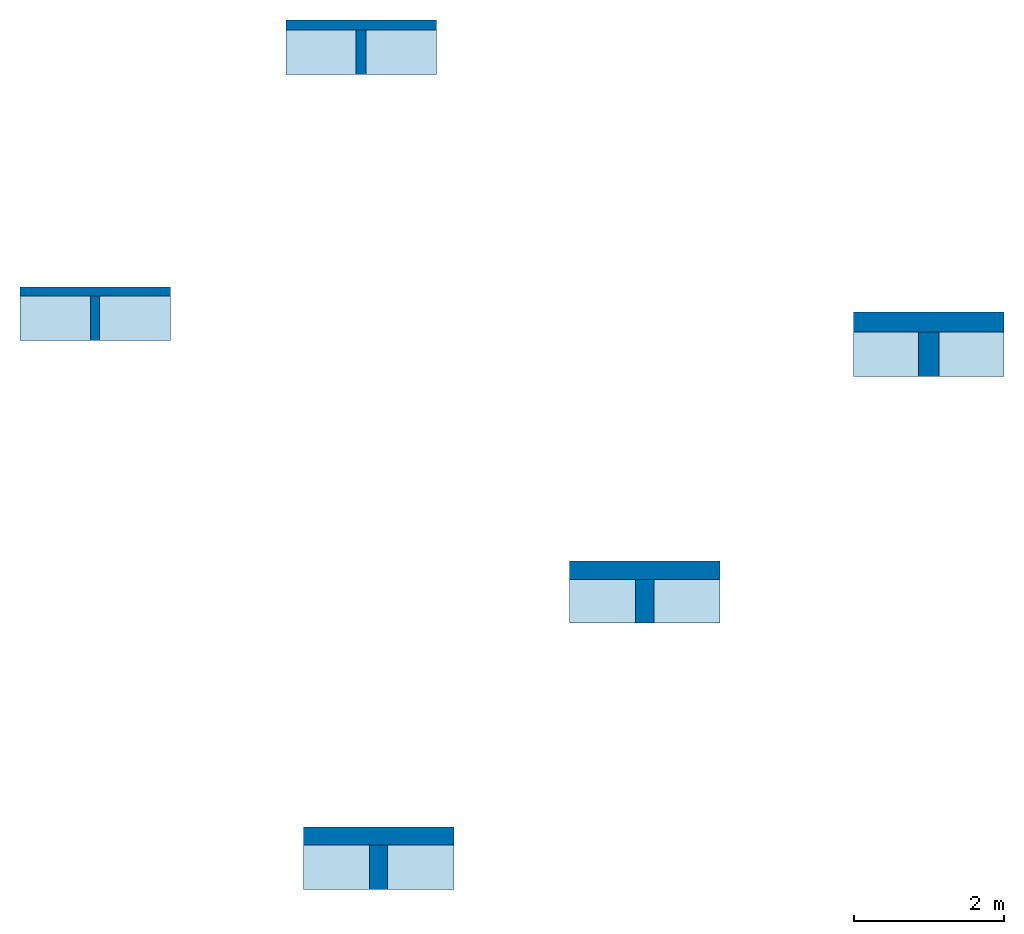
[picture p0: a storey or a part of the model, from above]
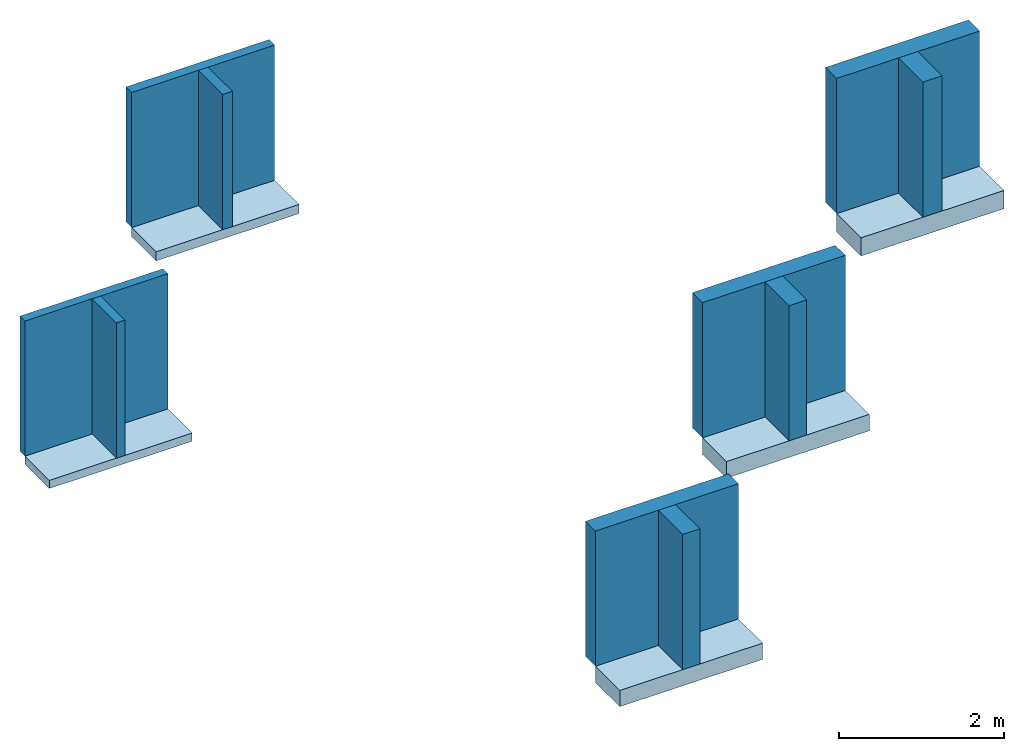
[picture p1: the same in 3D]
Properties of the parts of a building model (IFC2X3)

# File
Description: ViewDefinition [CoordinationView]
Time: 2023-01-18T10:33:11
Written by: The EXPRESS Data Manager Version 5.02.0100.07 : 28 Aug 2013
Made in: 21.1.70.21 - Exporter 21.1.70.21 - Alternate UI 21.1.70.21
Comment: STEP Physical File produced by: The EXPRESS Data Manager Version 5.02.0100.07 : 28 Aug 2013 * Module: EDMstepFileFactory/EDMstandAlone * Creation date: Wed Jan 18 10:33:11 2023 * Host: BIM-LT03 * Database: C:\Users\DONNEE~1\AppData\Local\Temp\6dfd9f73-01cb-4fe2-bb7c-203e315a706e\736068cb-28a9-4118-ab43-d0cfa3a6a8f2\ifc * Database version: 5507 * Database creation date: Wed Jan 18 10:33:10 2023 * Schema: IFC2X3 * Model: DataRepository.ifc * Model creation date: Wed Jan 18 10:33:11 2023 * Header model: DataRepository.ifc_HeaderModel * Header model creation date: Wed Jan 18 10:33:11 2023 * EDMuser: sdai-user * EDMgroup: sdai-group * License ID and type: 5605 : Permanent license. Expiry date: * EDMstepFileFactory options: 020000

# IfcSite, Default
RefLatitude: 42, 24, 53, 508911; RefLongitude: -71, -15, -29, -58837; RefElevation: 0 mm
Pset_ProductRequirements - Category: Project Information

# IfcBuilding
Pset_BuildingCommon - NumberOfStoreys: 2
Pset_ProductRequirements - Category: Project Information

# IfcBuildingStorey: Level:NL_00_niveau (2)
Pset_ProductRequirements - Category: Levels
Name | LongName = Pset_AirSideSystemInformation, Name = Pset_ProductRequirements, Name | Elevation (mm)
Begane grond | Begane grond | 0
Lengte | Lengte | 2000

# IfcRoof: Basic Roof:NLRS_27_RO_Naturoll 033_120x590x3300mm, Basic Roof:NLRS_27_RO_Naturoll 033_120x590x3300mm:5172
In: Lengte
Classification: 27 Daken (Uniformat)
Pset_ElementShading - Roughness: 304.8 mm
Pset_ManufacturerTypeInformation - Manufacturer: Knauf Insulation B.V.
Pset_ProductRequirements - Category: Roofs
Pset_QuantityTakeOff - Reference: Basic Roof:NLRS_27_RO_Naturoll 033_120x590x3300mm
Pset_RoofCommon - IsExternal: yes; Reference: Basic Roof:NLRS_27_RO_Naturoll 033_120x590x3300mm; ProjectedArea: 1.18 m2; TotalArea: 1.18 m2
Pset_Roof Schedule Naturoll 033 LOD400 - rollen / pak: 2; Type: Basic Roof: NLRS_27_RO_Naturoll 033_120x590x3300mm; Assembly Code: 27; Type Image: Raster image: Naturoll 033 .jpg (3); Model: Naturoll 033 is een onbeklede glaswoldeken met ECOSE® Technology; Manufacturer: Knauf Insulation B.V.; URL: www.knaufinsulation.nl; Description: Naturoll 033 - 120mm; phone: +31(0)162-421245; email: customerservice.nl@knaufinsulation.com; product URL: https://www.knaufinsulation.nl/producten-van-knauf-insulation/naturoll-033; warmteweerstand: 3.6; NLRS_C_Code_Brandklasse: A1; warmtegeleidingscoëfficiënt: 0.033; kortstondige waterabsorptie: WS; langdurige waterabsorptie: WL(P); luchtstroomweerstand: Afr10; DoP nummer (Declaration of performance): G4220NPCPR; NLRS_C_content_creator: Knauf Insulation; NLRS_C_content_versie: V1.0; diktebereik: 20 - 370; diktetolerantie: T4; pak (m2): 3.89; pakken / pallet: 24; pallet (m2): 93.36

# IfcRoof: Basic Roof:NLRS_27_RO_Naturoll 033_135x590x3900mm, Basic Roof:NLRS_27_RO_Naturoll 033_135x590x3900mm:5274
In: Lengte
Classification: 27 Daken (Uniformat)
Pset_ElementShading - Roughness: 304.8 mm
Pset_ManufacturerTypeInformation - Manufacturer: Knauf Insulation B.V.
Pset_ProductRequirements - Category: Roofs
Pset_QuantityTakeOff - Reference: Basic Roof:NLRS_27_RO_Naturoll 033_135x590x3900mm
Pset_RoofCommon - IsExternal: yes; Reference: Basic Roof:NLRS_27_RO_Naturoll 033_135x590x3900mm; ProjectedArea: 1.18 m2; TotalArea: 1.18 m2
Pset_Roof Schedule Naturoll 033 LOD400 - rollen / pak: 2; Type: Basic Roof: NLRS_27_RO_Naturoll 033_135x590x3900mm; Assembly Code: 27; Type Image: Raster image: Naturoll 033 .jpg (3); Model: Naturoll 033 is een onbeklede glaswoldeken met ECOSE® Technology; Manufacturer: Knauf Insulation B.V.; URL: www.knaufinsulation.nl; Description: Naturoll 033 - 135mm; phone: +31(0)162-421245; email: customerservice.nl@knaufinsulation.com; product URL: https://www.knaufinsulation.nl/producten-van-knauf-insulation/naturoll-033; warmteweerstand: 4.05; NLRS_C_Code_Brandklasse: A1; warmtegeleidingscoëfficiënt: 0.033; kortstondige waterabsorptie: WS; langdurige waterabsorptie: WL(P); luchtstroomweerstand: Afr10; DoP nummer (Declaration of performance): G4220NPCPR; NLRS_C_content_creator: Knauf Insulation; NLRS_C_content_versie: V1.0; diktebereik: 20 - 370; diktetolerantie: T4; pak (m2): 4.6; pakken / pallet: 24; pallet (m2): 110.45

# IfcRoof: Basic Roof:NLRS_27_RO_Naturoll 033_240x590x2000mm, Basic Roof:NLRS_27_RO_Naturoll 033_240x590x2000mm:11013
In: Lengte
Classification: 27 Daken (Uniformat)
Pset_ElementShading - Roughness: 304.8 mm
Pset_ManufacturerTypeInformation - Manufacturer: Knauf Insulation B.V.
Pset_ProductRequirements - Category: Roofs
Pset_QuantityTakeOff - Reference: Basic Roof:NLRS_27_RO_Naturoll 033_240x590x2000mm
Pset_RoofCommon - IsExternal: yes; Reference: Basic Roof:NLRS_27_RO_Naturoll 033_240x590x2000mm; ProjectedArea: 1.18 m2; TotalArea: 1.18 m2
Pset_Roof Schedule Naturoll 033 LOD400 - rollen / pak: 2; Type: Basic Roof: NLRS_27_RO_Naturoll 033_240x590x2000mm; Assembly Code: 27; Type Image: Raster image: Naturoll 033 .jpg (3); Model: Naturoll 033 is een onbeklede glaswoldeken met ECOSE® Technology; Manufacturer: Knauf Insulation B.V.; URL: www.knaufinsulation.nl; Description: Naturoll 033 - 240mm; phone: +31(0)162-421245; email: customerservice.nl@knaufinsulation.com; product URL: https://www.knaufinsulation.nl/producten-van-knauf-insulation/naturoll-033; warmteweerstand: 7.25; NLRS_C_Code_Brandklasse: A1; warmtegeleidingscoëfficiënt: 0.033; kortstondige waterabsorptie: WS; langdurige waterabsorptie: WL(P); luchtstroomweerstand: Afr10; DoP nummer (Declaration of performance): G4220NPCPR; NLRS_C_content_creator: Knauf Insulation; NLRS_C_content_versie: V1.0; diktebereik: 20 - 370; diktetolerantie: T4; pak (m2): 2.36; pakken / pallet: 24; pallet (m2): 56.64

# IfcRoof: Basic Roof:NLRS_27_RO_Naturoll 033_245x580x2000mm, Basic Roof:NLRS_27_RO_Naturoll 033_245x580x2000mm:11035
In: Lengte
Classification: 27 Daken (Uniformat)
Pset_ElementShading - Roughness: 304.8 mm
Pset_ManufacturerTypeInformation - Manufacturer: Knauf Insulation B.V.
Pset_ProductRequirements - Category: Roofs
Pset_QuantityTakeOff - Reference: Basic Roof:NLRS_27_RO_Naturoll 033_245x580x2000mm
Pset_RoofCommon - IsExternal: yes; Reference: Basic Roof:NLRS_27_RO_Naturoll 033_245x580x2000mm; ProjectedArea: 1.16 m2; TotalArea: 1.16 m2
Pset_Roof Schedule Naturoll 033 LOD400 - rollen / pak: 2; Type: Basic Roof: NLRS_27_RO_Naturoll 033_245x580x2000mm; Assembly Code: 27; Type Image: Raster image: Naturoll 033 .jpg (3); Model: Naturoll 033 is een onbeklede glaswoldeken met ECOSE® Technology; Manufacturer: Knauf Insulation B.V.; URL: www.knaufinsulation.nl; Description: Naturoll 033 - 245mm; phone: +31(0)162-421245; email: customerservice.nl@knaufinsulation.com; product URL: https://www.knaufinsulation.nl/producten-van-knauf-insulation/naturoll-033; warmteweerstand: 7.4; NLRS_C_Code_Brandklasse: A1; warmtegeleidingscoëfficiënt: 0.033; kortstondige waterabsorptie: WS; langdurige waterabsorptie: WL(P); luchtstroomweerstand: Afr10; DoP nummer (Declaration of performance): G4220NPCPR; NLRS_C_content_creator: Knauf Insulation; NLRS_C_content_versie: V1.0; diktebereik: 20 - 370; diktetolerantie: T4; pak (m2): 2.32; pakken / pallet: 24; pallet (m2): 55.68

# IfcRoof: Basic Roof:NLRS_27_RO_Naturoll 033_270x590x2500mm, Basic Roof:NLRS_27_RO_Naturoll 033_270x590x2500mm:11855
In: Lengte
Classification: 27 Daken (Uniformat)
Pset_ElementShading - Roughness: 304.8 mm
Pset_ManufacturerTypeInformation - Manufacturer: Knauf Insulation B.V.
Pset_ProductRequirements - Category: Roofs
Pset_QuantityTakeOff - Reference: Basic Roof:NLRS_27_RO_Naturoll 033_270x590x2500mm
Pset_RoofCommon - IsExternal: yes; Reference: Basic Roof:NLRS_27_RO_Naturoll 033_270x590x2500mm; ProjectedArea: 1.18 m2; TotalArea: 1.18 m2
Pset_Roof Schedule Naturoll 033 LOD400 - rollen / pak: 2; Type: Basic Roof: NLRS_27_RO_Naturoll 033_270x590x2500mm; Assembly Code: 27; Type Image: Raster image: Naturoll 033 .jpg (3); Model: Naturoll 033 is een onbeklede glaswoldeken met ECOSE® Technology; Manufacturer: Knauf Insulation B.V.; URL: www.knaufinsulation.nl; Description: Naturoll 033 - 270mm; phone: +31(0)162-421245; email: customerservice.nl@knaufinsulation.com; product URL: https://www.knaufinsulation.nl/producten-van-knauf-insulation/naturoll-033; warmteweerstand: 8.15; NLRS_C_Code_Brandklasse: A1; warmtegeleidingscoëfficiënt: 0.033; kortstondige waterabsorptie: WS; langdurige waterabsorptie: WL(P); luchtstroomweerstand: Afr10; DoP nummer (Declaration of performance): G4220NPCPR; NLRS_C_content_creator: Knauf Insulation; NLRS_C_content_versie: V1.0; diktebereik: 20 - 370; diktetolerantie: T4; pak (m2): 2.95; pakken / pallet: 18; pallet (m2): 53.1

# IfcSlab: Basic Roof:NLRS_27_RO_Naturoll 033_120x590x3300mm, Basic Roof:NLRS_27_RO_Naturoll 033_120x590x3300mm:5172
In: Lengte
Type - PredefinedType: ROOF
Type - Pset_ElementShading - Roughness: 304.8 mm
Type - Pset_ManufacturerTypeInformation - Manufacturer: Knauf Insulation B.V.
Type - Pset_ProductRequirements - Category: Roofs
Type - Pset_QuantityTakeOff - Reference: Basic Roof:NLRS_27_RO_Naturoll 033_120x590x3300mm
Type - Pset_ReinforcementBarPitchOfSlab - Description: Naturoll 033 - 120mm; Reference: Basic Roof:NLRS_27_RO_Naturoll 033_120x590x3300mm
Type - Pset_SlabCommon - IsExternal: yes; Reference: Basic Roof:NLRS_27_RO_Naturoll 033_120x590x3300mm; ThermalTransmittance: 0.275 kg/K/s3
Type - Pset_Roof Schedule Naturoll 033 LOD400 - rollen / pak: 2; Assembly Code: 27; Type Image: Raster image: Naturoll 033 .jpg (3); Model: Naturoll 033 is een onbeklede glaswoldeken met ECOSE® Technology; Manufacturer: Knauf Insulation B.V.; URL: www.knaufinsulation.nl; Description: Naturoll 033 - 120mm; phone: +31(0)162-421245; email: customerservice.nl@knaufinsulation.com; product URL: https://www.knaufinsulation.nl/producten-van-knauf-insulation/naturoll-033; warmteweerstand: 3.6; NLRS_C_Code_Brandklasse: A1; warmtegeleidingscoëfficiënt: 0.033; kortstondige waterabsorptie: WS; langdurige waterabsorptie: WL(P); luchtstroomweerstand: Afr10; DoP nummer (Declaration of performance): G4220NPCPR; NLRS_C_content_creator: Knauf Insulation; NLRS_C_content_versie: V1.0; diktebereik: 20 - 370; diktetolerantie: T4; pak (m2): 3.89; pakken / pallet: 24; pallet (m2): 93.36
Classification: 27 Daken (Uniformat); Material: Knauf Insulation_Ecose® glaswol Naturoll 033; Knauf Insulation_Ecose® glaswol Naturoll 033 120 mm
Pset_SlabCommon - PitchAngle: 0 deg
Pset_Roof Schedule Naturoll 033 LOD400 - Type: Basic Roof: NLRS_27_RO_Naturoll 033_120x590x3300mm

# IfcSlab: Basic Roof:NLRS_27_RO_Naturoll 033_135x590x3900mm, Basic Roof:NLRS_27_RO_Naturoll 033_135x590x3900mm:5274
In: Lengte
Type - PredefinedType: ROOF
Type - Pset_ElementShading - Roughness: 304.8 mm
Type - Pset_ManufacturerTypeInformation - Manufacturer: Knauf Insulation B.V.
Type - Pset_ProductRequirements - Category: Roofs
Type - Pset_QuantityTakeOff - Reference: Basic Roof:NLRS_27_RO_Naturoll 033_135x590x3900mm
Type - Pset_ReinforcementBarPitchOfSlab - Description: Naturoll 033 - 135mm; Reference: Basic Roof:NLRS_27_RO_Naturoll 033_135x590x3900mm
Type - Pset_SlabCommon - IsExternal: yes; Reference: Basic Roof:NLRS_27_RO_Naturoll 033_135x590x3900mm; ThermalTransmittance: 0.244444 kg/K/s3
Type - Pset_Roof Schedule Naturoll 033 LOD400 - rollen / pak: 2; Assembly Code: 27; Type Image: Raster image: Naturoll 033 .jpg (3); Model: Naturoll 033 is een onbeklede glaswoldeken met ECOSE® Technology; Manufacturer: Knauf Insulation B.V.; URL: www.knaufinsulation.nl; Description: Naturoll 033 - 135mm; phone: +31(0)162-421245; email: customerservice.nl@knaufinsulation.com; product URL: https://www.knaufinsulation.nl/producten-van-knauf-insulation/naturoll-033; warmteweerstand: 4.05; NLRS_C_Code_Brandklasse: A1; warmtegeleidingscoëfficiënt: 0.033; kortstondige waterabsorptie: WS; langdurige waterabsorptie: WL(P); luchtstroomweerstand: Afr10; DoP nummer (Declaration of performance): G4220NPCPR; NLRS_C_content_creator: Knauf Insulation; NLRS_C_content_versie: V1.0; diktebereik: 20 - 370; diktetolerantie: T4; pak (m2): 4.6; pakken / pallet: 24; pallet (m2): 110.45
Classification: 27 Daken (Uniformat); Material: Knauf Insulation_Ecose® glaswol Naturoll 033; Knauf Insulation_Ecose® glaswol Naturoll 033 135 mm
Pset_SlabCommon - PitchAngle: 0 deg
Pset_Roof Schedule Naturoll 033 LOD400 - Type: Basic Roof: NLRS_27_RO_Naturoll 033_135x590x3900mm

# IfcSlab: Basic Roof:NLRS_27_RO_Naturoll 033_240x590x2000mm, Basic Roof:NLRS_27_RO_Naturoll 033_240x590x2000mm:11013
In: Lengte
Type - PredefinedType: ROOF
Type - Pset_ElementShading - Roughness: 304.8 mm
Type - Pset_ManufacturerTypeInformation - Manufacturer: Knauf Insulation B.V.
Type - Pset_ProductRequirements - Category: Roofs
Type - Pset_QuantityTakeOff - Reference: Basic Roof:NLRS_27_RO_Naturoll 033_240x590x2000mm
Type - Pset_ReinforcementBarPitchOfSlab - Description: Naturoll 033 - 240mm; Reference: Basic Roof:NLRS_27_RO_Naturoll 033_240x590x2000mm
Type - Pset_SlabCommon - IsExternal: yes; Reference: Basic Roof:NLRS_27_RO_Naturoll 033_240x590x2000mm; ThermalTransmittance: 0.134694 kg/K/s3
Type - Pset_Roof Schedule Naturoll 033 LOD400 - rollen / pak: 2; Assembly Code: 27; Type Image: Raster image: Naturoll 033 .jpg (3); Model: Naturoll 033 is een onbeklede glaswoldeken met ECOSE® Technology; Manufacturer: Knauf Insulation B.V.; URL: www.knaufinsulation.nl; Description: Naturoll 033 - 240mm; phone: +31(0)162-421245; email: customerservice.nl@knaufinsulation.com; product URL: https://www.knaufinsulation.nl/producten-van-knauf-insulation/naturoll-033; warmteweerstand: 7.25; NLRS_C_Code_Brandklasse: A1; warmtegeleidingscoëfficiënt: 0.033; kortstondige waterabsorptie: WS; langdurige waterabsorptie: WL(P); luchtstroomweerstand: Afr10; DoP nummer (Declaration of performance): G4220NPCPR; NLRS_C_content_creator: Knauf Insulation; NLRS_C_content_versie: V1.0; diktebereik: 20 - 370; diktetolerantie: T4; pak (m2): 2.36; pakken / pallet: 24; pallet (m2): 56.64
Classification: 27 Daken (Uniformat); Material: Knauf Insulation_Ecose® glaswol Naturoll 033; Knauf Insulation_Ecose® glaswol Naturoll 033 245 mm
Pset_SlabCommon - PitchAngle: 0 deg
Pset_Roof Schedule Naturoll 033 LOD400 - Type: Basic Roof: NLRS_27_RO_Naturoll 033_240x590x2000mm

# IfcSlab: Basic Roof:NLRS_27_RO_Naturoll 033_245x580x2000mm, Basic Roof:NLRS_27_RO_Naturoll 033_245x580x2000mm:11035
In: Lengte
Type - PredefinedType: ROOF
Type - Pset_ElementShading - Roughness: 304.8 mm
Type - Pset_ManufacturerTypeInformation - Manufacturer: Knauf Insulation B.V.
Type - Pset_ProductRequirements - Category: Roofs
Type - Pset_QuantityTakeOff - Reference: Basic Roof:NLRS_27_RO_Naturoll 033_245x580x2000mm
Type - Pset_ReinforcementBarPitchOfSlab - Description: Naturoll 033 - 245mm; Reference: Basic Roof:NLRS_27_RO_Naturoll 033_245x580x2000mm
Type - Pset_SlabCommon - IsExternal: yes; Reference: Basic Roof:NLRS_27_RO_Naturoll 033_245x580x2000mm; ThermalTransmittance: 0.134694 kg/K/s3
Type - Pset_Roof Schedule Naturoll 033 LOD400 - rollen / pak: 2; Assembly Code: 27; Type Image: Raster image: Naturoll 033 .jpg (3); Model: Naturoll 033 is een onbeklede glaswoldeken met ECOSE® Technology; Manufacturer: Knauf Insulation B.V.; URL: www.knaufinsulation.nl; Description: Naturoll 033 - 245mm; phone: +31(0)162-421245; email: customerservice.nl@knaufinsulation.com; product URL: https://www.knaufinsulation.nl/producten-van-knauf-insulation/naturoll-033; warmteweerstand: 7.4; NLRS_C_Code_Brandklasse: A1; warmtegeleidingscoëfficiënt: 0.033; kortstondige waterabsorptie: WS; langdurige waterabsorptie: WL(P); luchtstroomweerstand: Afr10; DoP nummer (Declaration of performance): G4220NPCPR; NLRS_C_content_creator: Knauf Insulation; NLRS_C_content_versie: V1.0; diktebereik: 20 - 370; diktetolerantie: T4; pak (m2): 2.32; pakken / pallet: 24; pallet (m2): 55.68
Classification: 27 Daken (Uniformat); Material: Knauf Insulation_Ecose® glaswol Naturoll 033; Knauf Insulation_Ecose® glaswol Naturoll 033 245 mm
Pset_SlabCommon - PitchAngle: 0 deg
Pset_Roof Schedule Naturoll 033 LOD400 - Type: Basic Roof: NLRS_27_RO_Naturoll 033_245x580x2000mm

# IfcSlab: Basic Roof:NLRS_27_RO_Naturoll 033_270x590x2500mm, Basic Roof:NLRS_27_RO_Naturoll 033_270x590x2500mm:11855
In: Lengte
Type - PredefinedType: ROOF
Type - Pset_ElementShading - Roughness: 304.8 mm
Type - Pset_ManufacturerTypeInformation - Manufacturer: Knauf Insulation B.V.
Type - Pset_ProductRequirements - Category: Roofs
Type - Pset_QuantityTakeOff - Reference: Basic Roof:NLRS_27_RO_Naturoll 033_270x590x2500mm
Type - Pset_ReinforcementBarPitchOfSlab - Description: Naturoll 033 - 270mm; Reference: Basic Roof:NLRS_27_RO_Naturoll 033_270x590x2500mm
Type - Pset_SlabCommon - IsExternal: yes; Reference: Basic Roof:NLRS_27_RO_Naturoll 033_270x590x2500mm; ThermalTransmittance: 0.122222 kg/K/s3
Type - Pset_Roof Schedule Naturoll 033 LOD400 - rollen / pak: 2; Assembly Code: 27; Type Image: Raster image: Naturoll 033 .jpg (3); Model: Naturoll 033 is een onbeklede glaswoldeken met ECOSE® Technology; Manufacturer: Knauf Insulation B.V.; URL: www.knaufinsulation.nl; Description: Naturoll 033 - 270mm; phone: +31(0)162-421245; email: customerservice.nl@knaufinsulation.com; product URL: https://www.knaufinsulation.nl/producten-van-knauf-insulation/naturoll-033; warmteweerstand: 8.15; NLRS_C_Code_Brandklasse: A1; warmtegeleidingscoëfficiënt: 0.033; kortstondige waterabsorptie: WS; langdurige waterabsorptie: WL(P); luchtstroomweerstand: Afr10; DoP nummer (Declaration of performance): G4220NPCPR; NLRS_C_content_creator: Knauf Insulation; NLRS_C_content_versie: V1.0; diktebereik: 20 - 370; diktetolerantie: T4; pak (m2): 2.95; pakken / pallet: 18; pallet (m2): 53.1
Classification: 27 Daken (Uniformat); Material: Knauf Insulation_Ecose® glaswol Naturoll 033; Knauf Insulation_Ecose® glaswol Naturoll 033 270 mm
Pset_SlabCommon - PitchAngle: 0 deg
Pset_Roof Schedule Naturoll 033 LOD400 - Type: Basic Roof: NLRS_27_RO_Naturoll 033_270x590x2500mm

# IfcSlab: Floor:NLRS_23_FL_Naturoll 033_120x590x3300mm, Floor:NLRS_23_FL_Naturoll 033_120x590x3300mm:4805
In: Begane grond
Type - PredefinedType: FLOOR; Material: Knauf Insulation_Ecose® glaswol Naturoll 033 120 mm
Type - Pset_ElementShading - Roughness: 304.8 mm
Type - Pset_ManufacturerTypeInformation - Manufacturer: Knauf Insulation B.V.
Type - Pset_ProductRequirements - Category: Floors
Type - Pset_QuantityTakeOff - Reference: Floor:NLRS_23_FL_Naturoll 033_120x590x3300mm
Type - Pset_ReinforcementBarPitchOfSlab - Description: Naturoll 033 - 120mm; Reference: Floor:NLRS_23_FL_Naturoll 033_120x590x3300mm
Type - Pset_SlabCommon - Reference: Floor:NLRS_23_FL_Naturoll 033_120x590x3300mm; IsExternal: no; ThermalTransmittance: 0.275 kg/K/s3
Type - Pset_Floor Schedule Naturoll 033 LOD400 - rollen / pak: 2; Assembly Code: 23; Type Image: Raster image: Naturoll 033 .jpg (3); Model: Naturoll 033 is een onbeklede glaswoldeken met ECOSE® Technology; Manufacturer: Knauf Insulation B.V.; URL: www.knaufinsulation.nl; Description: Naturoll 033 - 120mm; phone: +31(0)162-421245; email: customerservice.nl@knaufinsulation.com; product URL: https://www.knaufinsulation.nl/producten-van-knauf-insulation/naturoll-033; warmteweerstand: 3.6; NLRS_C_Code_Brandklasse: A1; warmtegeleidingscoëfficiënt: 0.033; kortstondige waterabsorptie: WS; langdurige waterabsorptie: WL(P); luchtstroomweerstand: Afr10; DoP nummer (Declaration of performance): G4220NPCPR; NLRS_C_content_creator: Knauf Insulation; NLRS_C_content_versie: V1.0; diktebereik: 20 - 370; diktetolerantie: T4; pak (m2): 3.89; pakken / pallet: 24; pallet (m2): 93.36
Classification: 23 Vloeren (Uniformat)
Pset_SlabCommon - LoadBearing: no; PitchAngle: 0 deg
Pset_Floor Schedule Naturoll 033 LOD400 - Type: Floor: NLRS_23_FL_Naturoll 033_120x590x3300mm

# IfcSlab: Floor:NLRS_23_FL_Naturoll 033_135x590x3900mm, Floor:NLRS_23_FL_Naturoll 033_135x590x3900mm:5263
In: Begane grond
Type - PredefinedType: FLOOR; Material: Knauf Insulation_Ecose® glaswol Naturoll 033 135 mm
Type - Pset_ElementShading - Roughness: 304.8 mm
Type - Pset_ManufacturerTypeInformation - Manufacturer: Knauf Insulation B.V.
Type - Pset_ProductRequirements - Category: Floors
Type - Pset_QuantityTakeOff - Reference: Floor:NLRS_23_FL_Naturoll 033_135x590x3900mm
Type - Pset_ReinforcementBarPitchOfSlab - Description: Naturoll 033 - 135mm; Reference: Floor:NLRS_23_FL_Naturoll 033_135x590x3900mm
Type - Pset_SlabCommon - IsExternal: no; Reference: Floor:NLRS_23_FL_Naturoll 033_135x590x3900mm; ThermalTransmittance: 0.244444 kg/K/s3
Type - Pset_Floor Schedule Naturoll 033 LOD400 - rollen / pak: 2; Assembly Code: 23; Type Image: Raster image: Naturoll 033 .jpg (3); Model: Naturoll 033 is een onbeklede glaswoldeken met ECOSE® Technology; Manufacturer: Knauf Insulation B.V.; URL: www.knaufinsulation.nl; Description: Naturoll 033 - 135mm; phone: +31(0)162-421245; email: customerservice.nl@knaufinsulation.com; product URL: https://www.knaufinsulation.nl/producten-van-knauf-insulation/naturoll-033; warmteweerstand: 4.05; NLRS_C_Code_Brandklasse: A1; warmtegeleidingscoëfficiënt: 0.033; kortstondige waterabsorptie: WS; langdurige waterabsorptie: WL(P); luchtstroomweerstand: Afr10; DoP nummer (Declaration of performance): G4220NPCPR; NLRS_C_content_creator: Knauf Insulation; NLRS_C_content_versie: V1.0; diktebereik: 20 - 370; diktetolerantie: T4; pak (m2): 4.6; pakken / pallet: 24; pallet (m2): 110.45
Classification: 23 Vloeren (Uniformat)
Pset_SlabCommon - LoadBearing: no; PitchAngle: 0 deg
Pset_Floor Schedule Naturoll 033 LOD400 - Type: Floor: NLRS_23_FL_Naturoll 033_135x590x3900mm

# IfcSlab: Floor:NLRS_23_FL_Naturoll 033_240x590x2000mm, Floor:NLRS_23_FL_Naturoll 033_240x590x2000mm:11002
In: Begane grond
Type - PredefinedType: FLOOR; Material: Knauf Insulation_Ecose® glaswol Naturoll 033 240 mm
Type - Pset_ElementShading - Roughness: 304.8 mm
Type - Pset_ManufacturerTypeInformation - Manufacturer: Knauf Insulation B.V.
Type - Pset_ProductRequirements - Category: Floors
Type - Pset_QuantityTakeOff - Reference: Floor:NLRS_23_FL_Naturoll 033_240x590x2000mm
Type - Pset_ReinforcementBarPitchOfSlab - Description: Naturoll 033 - 240mm; Reference: Floor:NLRS_23_FL_Naturoll 033_240x590x2000mm
Type - Pset_SlabCommon - IsExternal: no; Reference: Floor:NLRS_23_FL_Naturoll 033_240x590x2000mm; ThermalTransmittance: 0.1375 kg/K/s3
Type - Pset_Floor Schedule Naturoll 033 LOD400 - rollen / pak: 2; Assembly Code: 23; Type Image: Raster image: Naturoll 033 .jpg (3); Model: Naturoll 033 is een onbeklede glaswoldeken met ECOSE® Technology; Manufacturer: Knauf Insulation B.V.; URL: www.knaufinsulation.nl; Description: Naturoll 033 - 240mm; phone: +31(0)162-421245; email: customerservice.nl@knaufinsulation.com; product URL: https://www.knaufinsulation.nl/producten-van-knauf-insulation/naturoll-033; warmteweerstand: 7.25; NLRS_C_Code_Brandklasse: A1; warmtegeleidingscoëfficiënt: 0.033; kortstondige waterabsorptie: WS; langdurige waterabsorptie: WL(P); luchtstroomweerstand: Afr10; DoP nummer (Declaration of performance): G4220NPCPR; NLRS_C_content_creator: Knauf Insulation; NLRS_C_content_versie: V1.0; diktebereik: 20 - 370; diktetolerantie: T4; pak (m2): 2.36; pakken / pallet: 24; pallet (m2): 56.64
Classification: 23 Vloeren (Uniformat)
Pset_SlabCommon - LoadBearing: no; PitchAngle: 0 deg
Pset_Floor Schedule Naturoll 033 LOD400 - Type: Floor: NLRS_23_FL_Naturoll 033_240x590x2000mm

# IfcSlab: Floor:NLRS_23_FL_Naturoll 033_245x580x2000mm, Floor:NLRS_23_FL_Naturoll 033_245x580x2000mm:11025
In: Begane grond
Type - PredefinedType: FLOOR; Material: Knauf Insulation_Ecose® glaswol Naturoll 033 245 mm
Type - Pset_ElementShading - Roughness: 304.8 mm
Type - Pset_ManufacturerTypeInformation - Manufacturer: Knauf Insulation B.V.
Type - Pset_ProductRequirements - Category: Floors
Type - Pset_QuantityTakeOff - Reference: Floor:NLRS_23_FL_Naturoll 033_245x580x2000mm
Type - Pset_ReinforcementBarPitchOfSlab - Description: Naturoll 033 - 245mm; Reference: Floor:NLRS_23_FL_Naturoll 033_245x580x2000mm
Type - Pset_SlabCommon - IsExternal: no; Reference: Floor:NLRS_23_FL_Naturoll 033_245x580x2000mm; ThermalTransmittance: 0.134694 kg/K/s3
Type - Pset_Floor Schedule Naturoll 033 LOD400 - rollen / pak: 2; Assembly Code: 23; Type Image: Raster image: Naturoll 033 .jpg (3); Model: Naturoll 033 is een onbeklede glaswoldeken met ECOSE® Technology; Manufacturer: Knauf Insulation B.V.; URL: www.knaufinsulation.nl; Description: Naturoll 033 - 245mm; phone: +31(0)162-421245; email: customerservice.nl@knaufinsulation.com; product URL: https://www.knaufinsulation.nl/producten-van-knauf-insulation/naturoll-033; warmteweerstand: 7.4; NLRS_C_Code_Brandklasse: A1; warmtegeleidingscoëfficiënt: 0.033; kortstondige waterabsorptie: WS; langdurige waterabsorptie: WL(P); luchtstroomweerstand: Afr10; DoP nummer (Declaration of performance): G4220NPCPR; NLRS_C_content_creator: Knauf Insulation; NLRS_C_content_versie: V1.0; diktebereik: 20 - 370; diktetolerantie: T4; pak (m2): 2.32; pakken / pallet: 24; pallet (m2): 55.68
Classification: 23 Vloeren (Uniformat)
Pset_SlabCommon - LoadBearing: no; PitchAngle: 0 deg
Pset_Floor Schedule Naturoll 033 LOD400 - Type: Floor: NLRS_23_FL_Naturoll 033_245x580x2000mm

# IfcSlab: Floor:NLRS_23_FL_Naturoll 033_270x590x2500mm, Floor:NLRS_23_FL_Naturoll 033_270x590x2500mm:11844
In: Begane grond
Type - PredefinedType: FLOOR; Material: Knauf Insulation_Ecose® glaswol Naturoll 033 270 mm
Type - Pset_ElementShading - Roughness: 304.8 mm
Type - Pset_ManufacturerTypeInformation - Manufacturer: Knauf Insulation B.V.
Type - Pset_ProductRequirements - Category: Floors
Type - Pset_QuantityTakeOff - Reference: Floor:NLRS_23_FL_Naturoll 033_270x590x2500mm
Type - Pset_ReinforcementBarPitchOfSlab - Description: Naturoll 033 - 270mm; Reference: Floor:NLRS_23_FL_Naturoll 033_270x590x2500mm
Type - Pset_SlabCommon - IsExternal: no; Reference: Floor:NLRS_23_FL_Naturoll 033_270x590x2500mm; ThermalTransmittance: 0.122222 kg/K/s3
Type - Pset_Floor Schedule Naturoll 033 LOD400 - rollen / pak: 2; Assembly Code: 23; Type Image: Raster image: Naturoll 033 .jpg (3); Model: Naturoll 033 is een onbeklede glaswoldeken met ECOSE® Technology; Manufacturer: Knauf Insulation B.V.; URL: www.knaufinsulation.nl; Description: Naturoll 033 - 270mm; phone: +31(0)162-421245; email: customerservice.nl@knaufinsulation.com; product URL: https://www.knaufinsulation.nl/producten-van-knauf-insulation/naturoll-033; warmteweerstand: 8.15; NLRS_C_Code_Brandklasse: A1; warmtegeleidingscoëfficiënt: 0.033; kortstondige waterabsorptie: WS; langdurige waterabsorptie: WL(P); luchtstroomweerstand: Afr10; DoP nummer (Declaration of performance): G4220NPCPR; NLRS_C_content_creator: Knauf Insulation; NLRS_C_content_versie: V1.0; diktebereik: 20 - 370; diktetolerantie: T4; pak (m2): 2.95; pakken / pallet: 18; pallet (m2): 53.1
Classification: 23 Vloeren (Uniformat)
Pset_SlabCommon - LoadBearing: no; PitchAngle: 0 deg
Pset_Floor Schedule Naturoll 033 LOD400 - Type: Floor: NLRS_23_FL_Naturoll 033_270x590x2500mm

# IfcWallStandardCase: Basic Wall:NLRS_21_WA_Naturoll 033_120x590x3300mm (2)
In: Begane grond
Type - PredefinedType: STANDARD; Material: Knauf Insulation_Ecose® glaswol Naturoll 033 120 mm
Type - Pset_ElementShading - Roughness: 304.8 mm
Type - Pset_ManufacturerTypeInformation - Manufacturer: Knauf Insulation B.V.
Type - Pset_ProductRequirements - Category: Walls
Type - Pset_QuantityTakeOff - Reference: Basic Wall:NLRS_21_WA_Naturoll 033_120x590x3300mm
Type - Pset_ReinforcementBarPitchOfWall - Description: Naturoll 033 - 120mm; Reference: Basic Wall:NLRS_21_WA_Naturoll 033_120x590x3300mm
Type - Pset_WallCommon - IsExternal: no; Reference: Basic Wall:NLRS_21_WA_Naturoll 033_120x590x3300mm; ThermalTransmittance: 0.275 kg/K/s3
Type - Pset_Wall Schedule Naturoll 033 LOD400 - rollen / pak: 2; Assembly Code: 21; Type Image: Raster image: Naturoll 033 .jpg (3); Model: Naturoll 033 is een onbeklede glaswoldeken met ECOSE® Technology; Manufacturer: Knauf Insulation B.V.; URL: www.knaufinsulation.nl; Description: Naturoll 033 - 120mm; phone: +31(0)162-421245; email: customerservice.nl@knaufinsulation.com; product URL: https://www.knaufinsulation.nl/producten-van-knauf-insulation/naturoll-033; warmteweerstand: 3.6; NLRS_C_Code_Brandklasse: A1; warmtegeleidingscoëfficiënt: 0.033; kortstondige waterabsorptie: WS; langdurige waterabsorptie: WL(P); luchtstroomweerstand: Afr10; DoP nummer (Declaration of performance): G4220NPCPR; NLRS_C_content_creator: Knauf Insulation; NLRS_C_content_versie: V1.0; diktebereik: 20 - 370; diktetolerantie: T4; pak (m2): 3.89; pakken / pallet: 24; pallet (m2): 93.36
Classification: 21 Buitenwanden (Uniformat)
Pset_WallCommon - LoadBearing: no; IsExternal: yes; ExtendToStructure: no
Pset_Wall Schedule Naturoll 033 LOD400 - Type: Basic Wall: NLRS_21_WA_Naturoll 033_120x590x3300mm
Name (Basic Wall:NLRS_21_WA_Naturoll 033_120x590x3300mm:...)
4861
4961

# IfcWallStandardCase: Basic Wall:NLRS_21_WA_Naturoll 033_135x590x3900mm (2)
In: Begane grond
Type - PredefinedType: STANDARD; Material: Knauf Insulation_Ecose® glaswol Naturoll 033 135 mm
Type - Pset_ElementShading - Roughness: 304.8 mm
Type - Pset_ManufacturerTypeInformation - Manufacturer: Knauf Insulation B.V.
Type - Pset_ProductRequirements - Category: Walls
Type - Pset_QuantityTakeOff - Reference: Basic Wall:NLRS_21_WA_Naturoll 033_135x590x3900mm
Type - Pset_ReinforcementBarPitchOfWall - Description: Naturoll 033 - 135mm; Reference: Basic Wall:NLRS_21_WA_Naturoll 033_135x590x3900mm
Type - Pset_WallCommon - IsExternal: no; Reference: Basic Wall:NLRS_21_WA_Naturoll 033_135x590x3900mm; ThermalTransmittance: 0.244444 kg/K/s3
Type - Pset_Wall Schedule Naturoll 033 LOD400 - rollen / pak: 2; Assembly Code: 21; Type Image: Raster image: Naturoll 033 .jpg (3); Model: Naturoll 033 is een onbeklede glaswoldeken met ECOSE® Technology; Manufacturer: Knauf Insulation B.V.; URL: www.knaufinsulation.nl; Description: Naturoll 033 - 135mm; phone: +31(0)162-421245; email: customerservice.nl@knaufinsulation.com; product URL: https://www.knaufinsulation.nl/producten-van-knauf-insulation/naturoll-033; warmteweerstand: 4.05; NLRS_C_Code_Brandklasse: A1; warmtegeleidingscoëfficiënt: 0.033; kortstondige waterabsorptie: WS; langdurige waterabsorptie: WL(P); luchtstroomweerstand: Afr10; DoP nummer (Declaration of performance): G4220NPCPR; NLRS_C_content_creator: Knauf Insulation; NLRS_C_content_versie: V1.0; diktebereik: 20 - 370; diktetolerantie: T4; pak (m2): 4.6; pakken / pallet: 24; pallet (m2): 110.45
Classification: 21 Buitenwanden (Uniformat)
Pset_WallCommon - LoadBearing: no; IsExternal: yes; ExtendToStructure: no
Pset_Wall Schedule Naturoll 033 LOD400 - Type: Basic Wall: NLRS_21_WA_Naturoll 033_135x590x3900mm
Name (Basic Wall:NLRS_21_WA_Naturoll 033_135x590x3900mm:...)
5268
5269

# IfcWallStandardCase: Basic Wall:NLRS_21_WA_Naturoll 033_240x590x2000mm (2)
In: Begane grond
Type - PredefinedType: STANDARD; Material: Knauf Insulation_Ecose® glaswol Naturoll 033 240 mm
Type - Pset_ElementShading - Roughness: 304.8 mm
Type - Pset_ManufacturerTypeInformation - Manufacturer: Knauf Insulation B.V.
Type - Pset_ProductRequirements - Category: Walls
Type - Pset_QuantityTakeOff - Reference: Basic Wall:NLRS_21_WA_Naturoll 033_240x590x2000mm
Type - Pset_ReinforcementBarPitchOfWall - Description: Naturoll 033 - 240mm; Reference: Basic Wall:NLRS_21_WA_Naturoll 033_240x590x2000mm
Type - Pset_WallCommon - IsExternal: no; Reference: Basic Wall:NLRS_21_WA_Naturoll 033_240x590x2000mm; ThermalTransmittance: 0.1375 kg/K/s3
Type - Pset_Wall Schedule Naturoll 033 LOD400 - rollen / pak: 2; Assembly Code: 21; Type Image: Raster image: Naturoll 033 .jpg (3); Model: Naturoll 033 is een onbeklede glaswoldeken met ECOSE® Technology; Manufacturer: Knauf Insulation B.V.; URL: www.knaufinsulation.nl; Description: Naturoll 033 - 240mm; phone: +31(0)162-421245; email: customerservice.nl@knaufinsulation.com; product URL: https://www.knaufinsulation.nl/producten-van-knauf-insulation/naturoll-033; warmteweerstand: 7.25; NLRS_C_Code_Brandklasse: A1; warmtegeleidingscoëfficiënt: 0.033; kortstondige waterabsorptie: WS; langdurige waterabsorptie: WL(P); luchtstroomweerstand: Afr10; DoP nummer (Declaration of performance): G4220NPCPR; NLRS_C_content_creator: Knauf Insulation; NLRS_C_content_versie: V1.0; diktebereik: 20 - 370; diktetolerantie: T4; pak (m2): 2.36; pakken / pallet: 24; pallet (m2): 56.64
Classification: 21 Buitenwanden (Uniformat)
Pset_WallCommon - LoadBearing: no; IsExternal: yes; ExtendToStructure: no
Pset_Wall Schedule Naturoll 033 LOD400 - Type: Basic Wall: NLRS_21_WA_Naturoll 033_240x590x2000mm
Name (Basic Wall:NLRS_21_WA_Naturoll 033_240x590x2000mm:...)
11007
11008

# IfcWallStandardCase: Basic Wall:NLRS_21_WA_Naturoll 033_245x580x2000mm (2)
In: Begane grond
Type - PredefinedType: STANDARD; Material: Knauf Insulation_Ecose® glaswol Naturoll 033 245 mm
Type - Pset_ElementShading - Roughness: 304.8 mm
Type - Pset_ManufacturerTypeInformation - Manufacturer: Knauf Insulation B.V.
Type - Pset_ProductRequirements - Category: Walls
Type - Pset_QuantityTakeOff - Reference: Basic Wall:NLRS_21_WA_Naturoll 033_245x580x2000mm
Type - Pset_ReinforcementBarPitchOfWall - Description: Naturoll 033 - 245mm; Reference: Basic Wall:NLRS_21_WA_Naturoll 033_245x580x2000mm
Type - Pset_WallCommon - IsExternal: no; Reference: Basic Wall:NLRS_21_WA_Naturoll 033_245x580x2000mm; ThermalTransmittance: 0.134694 kg/K/s3
Type - Pset_Wall Schedule Naturoll 033 LOD400 - rollen / pak: 2; Assembly Code: 21; Type Image: Raster image: Naturoll 033 .jpg (3); Model: Naturoll 033 is een onbeklede glaswoldeken met ECOSE® Technology; Manufacturer: Knauf Insulation B.V.; URL: www.knaufinsulation.nl; Description: Naturoll 033 - 245mm; phone: +31(0)162-421245; email: customerservice.nl@knaufinsulation.com; product URL: https://www.knaufinsulation.nl/producten-van-knauf-insulation/naturoll-033; warmteweerstand: 7.4; NLRS_C_Code_Brandklasse: A1; warmtegeleidingscoëfficiënt: 0.033; kortstondige waterabsorptie: WS; langdurige waterabsorptie: WL(P); luchtstroomweerstand: Afr10; DoP nummer (Declaration of performance): G4220NPCPR; NLRS_C_content_creator: Knauf Insulation; NLRS_C_content_versie: V1.0; diktebereik: 20 - 370; diktetolerantie: T4; pak (m2): 2.32; pakken / pallet: 24; pallet (m2): 55.68
Classification: 21 Buitenwanden (Uniformat)
Pset_WallCommon - LoadBearing: no; IsExternal: yes; ExtendToStructure: no
Pset_Wall Schedule Naturoll 033 LOD400 - Type: Basic Wall: NLRS_21_WA_Naturoll 033_245x580x2000mm
Name (Basic Wall:NLRS_21_WA_Naturoll 033_245x580x2000mm:...)
11030
11031

# IfcWallStandardCase: Basic Wall:NLRS_21_WA_Naturoll 033_270x590x2500mm (2)
In: Begane grond
Type - PredefinedType: STANDARD; Material: Knauf Insulation_Ecose® glaswol Naturoll 033 270 mm
Type - Pset_ElementShading - Roughness: 304.8 mm
Type - Pset_ManufacturerTypeInformation - Manufacturer: Knauf Insulation B.V.
Type - Pset_ProductRequirements - Category: Walls
Type - Pset_QuantityTakeOff - Reference: Basic Wall:NLRS_21_WA_Naturoll 033_270x590x2500mm
Type - Pset_ReinforcementBarPitchOfWall - Description: Naturoll 033 - 270mm; Reference: Basic Wall:NLRS_21_WA_Naturoll 033_270x590x2500mm
Type - Pset_WallCommon - IsExternal: no; Reference: Basic Wall:NLRS_21_WA_Naturoll 033_270x590x2500mm; ThermalTransmittance: 0.122222 kg/K/s3
Type - Pset_Wall Schedule Naturoll 033 LOD400 - rollen / pak: 2; Assembly Code: 21; Type Image: Raster image: Naturoll 033 .jpg (3); Model: Naturoll 033 is een onbeklede glaswoldeken met ECOSE® Technology; Manufacturer: Knauf Insulation B.V.; URL: www.knaufinsulation.nl; Description: Naturoll 033 - 270mm; phone: +31(0)162-421245; email: customerservice.nl@knaufinsulation.com; product URL: https://www.knaufinsulation.nl/producten-van-knauf-insulation/naturoll-033; warmteweerstand: 8.15; NLRS_C_Code_Brandklasse: A1; warmtegeleidingscoëfficiënt: 0.033; kortstondige waterabsorptie: WS; langdurige waterabsorptie: WL(P); luchtstroomweerstand: Afr10; DoP nummer (Declaration of performance): G4220NPCPR; NLRS_C_content_creator: Knauf Insulation; NLRS_C_content_versie: V1.0; diktebereik: 20 - 370; diktetolerantie: T4; pak (m2): 2.95; pakken / pallet: 18; pallet (m2): 53.1
Classification: 21 Buitenwanden (Uniformat)
Pset_WallCommon - LoadBearing: no; IsExternal: yes; ExtendToStructure: no
Pset_Wall Schedule Naturoll 033 LOD400 - Type: Basic Wall: NLRS_21_WA_Naturoll 033_270x590x2500mm
Name (Basic Wall:NLRS_21_WA_Naturoll 033_270x590x2500mm:...)
11849
11850
